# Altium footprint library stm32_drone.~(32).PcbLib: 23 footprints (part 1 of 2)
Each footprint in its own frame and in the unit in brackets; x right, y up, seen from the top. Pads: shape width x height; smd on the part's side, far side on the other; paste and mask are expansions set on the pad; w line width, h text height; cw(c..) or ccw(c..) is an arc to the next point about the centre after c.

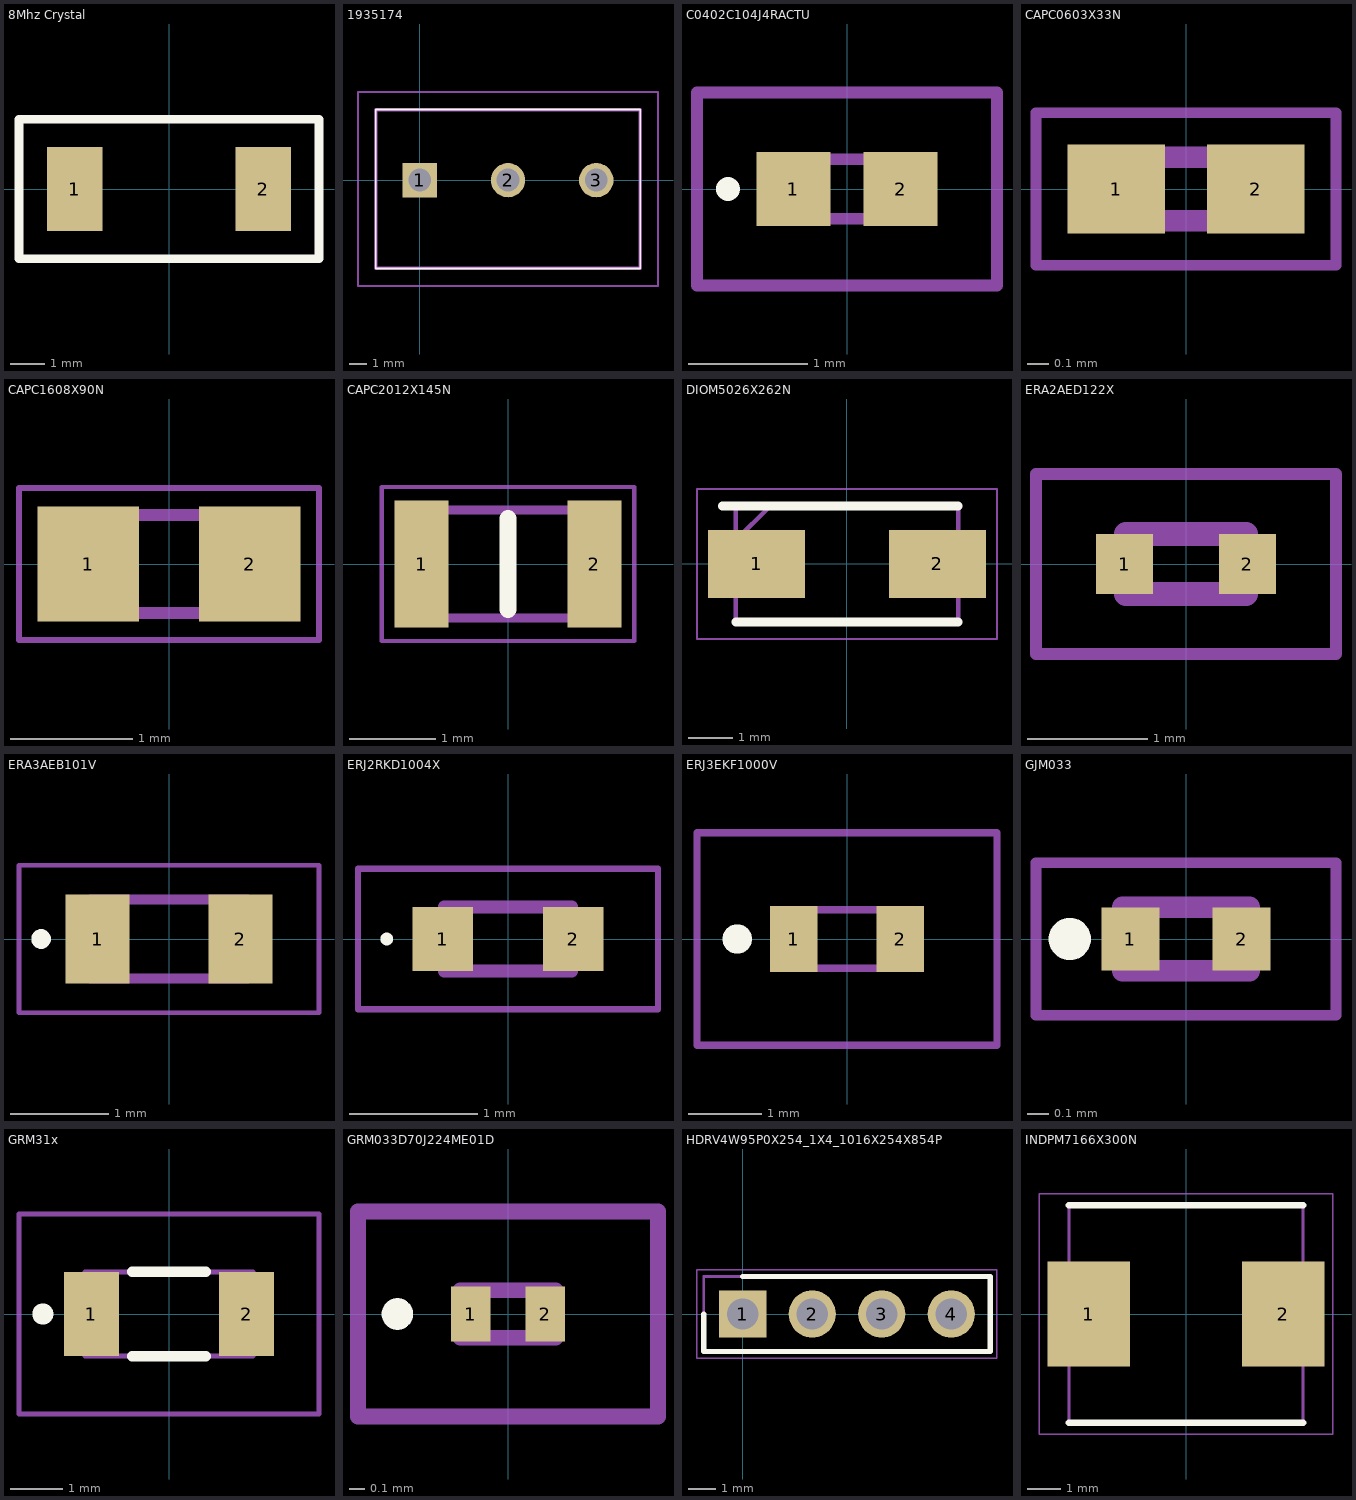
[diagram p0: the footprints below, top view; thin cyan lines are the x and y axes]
## 8Mhz Crystal [mm]
pads (2):
  rect 1.6x2.4 smd: 1(-2.7,0) 2(2.7,0)
Top Overlay:
  lines w0.25: -4.3,-2 -4.3,0 -4.3,2 4.3,2 4.3,-2 -4.3,-2
3D body "XTAL_H130A_RAL.step": height 1.09, standoff 0, extent -2.864,-2.089 2.864,2.089

## 1935174 [mm]
pads (3):
  rect 1.95x1.95 hole 1.3: 1(0,0)
  round 1.95 hole 1.3: 2(5,0) 3(10,0)
Top Overlay:
  lines w0.1: -2.5,-5 12.5,-5 12.5,4 -2.5,4 -2.5,-5
Mechanical 13:
  lines w0.2: -2.5,-5 12.5,-5 12.5,4 -2.5,4 -2.5,-5
Mechanical 15:
  lines w0.1: -3.5,-6 13.5,-6 13.5,5 -3.5,5 -3.5,-6
3D body "1935174.stp": height 11.63, standoff -3.27, extent -2.47,-5 12.93,4

## C0402C104J4RACTU [mm]
pads (2):
  rect 0.62x0.62 smd: 1(-0.45,0) 2(0.45,0)
Top Overlay:
  lines w0.1: -1,-0.05 ccw(c-1,0) -1,0.05 ccw(c-1,0) -1,-0.05
Mechanical 13:
  lines w0.1: -0.5,-0.25 -0.5,0.25 0.5,0.25 0.5,-0.25 -0.5,-0.25
Mechanical 15:
  lines w0.1: -1.26,-0.81 -1.26,0.81 1.26,0.81 1.26,-0.81 -1.26,-0.81
3D body "C0402C102J5GECTU.stp": height 0.55, standoff 0, extent -0.52,-0.28 0.53,0.27

## CAPC0603X33N [mm]
pads (2):
  rect 0.46x0.42 smd: 1(-0.33,0) 2(0.33,0)
Mechanical 13:
  lines w0.1: -0.3,-0.15 -0.3,0.15 0.3,0.15 0.3,-0.15 -0.3,-0.15
Mechanical 15:
  lines w0.05: -0.71,-0.36 -0.71,0.36 0.71,0.36 0.71,-0.36 -0.71,-0.36
3D body "GRM0335C1H101JA01D.stp": height 0.33, standoff 0, extent -0.3,-0.15 0.3,0.15

## CAPC1608X90N [mm]
pads (2):
  rect 0.83x0.94 smd: 1(-0.66,0) 2(0.66,0)
Mechanical 13:
  lines w0.1: -0.8,-0.4 0.8,-0.4 0.8,0.4 -0.8,0.4 -0.8,-0.4
Mechanical 15:
  lines w0.05: -1.225,-0.62 1.225,-0.62 1.225,0.62 -1.225,0.62 -1.225,-0.62
3D body "CC0603KRX5R8BB105.stp": height 0.9, standoff 0, extent -0.85,-0.45 0.85,0.45

## CAPC2012X145N [mm]
pads (2):
  rect 0.62x1.47 smd: 1(-1,0) 2(1,0)
Top Overlay:
  lines w0.2: 0,-0.525 0,0.525
Mechanical 13:
  lines w0.1: -1,-0.625 1,-0.625 1,0.625 -1,0.625 -1,-0.625
Mechanical 15:
  lines w0.05: -1.46,-0.89 1.46,-0.89 1.46,0.89 -1.46,0.89 -1.46,-0.89
3D body "C2012X5R1V226M125AC.stp": height 1.25, standoff 0, extent -1,-0.8 1,0.8

## DIOM5026X262N [mm]
pads (2):
  rect 2.2x1.55 smd: 1(-2.05,0) 2(2.05,0)
Top Overlay:
  lines w0.2: -2.825,1.312 2.52,1.312 ; -2.52,-1.312 2.52,-1.312
Mechanical 13:
  lines w0.1: -2.52,0.538 -1.745,1.312 ; -2.52,-1.312 2.52,-1.312 2.52,1.312 -2.52,1.312 -2.52,-1.312
Mechanical 15:
  lines w0.05: -3.4,-1.7 3.4,-1.7 3.4,1.7 -3.4,1.7 -3.4,-1.7
3D body "SS14.stp": height 2.62, standoff 0, extent -2.52,-1.312 2.52,1.312

## ERA2AED122X [mm]
pads (2):
  rect 0.475x0.5 smd: 1(-0.512,0) 2(0.512,0)
Mechanical 13:
  lines w0.2: -0.5,-0.25 0.5,-0.25 0.5,0.25 -0.5,0.25 -0.5,-0.25
Mechanical 15:
  lines w0.1: -1.25,-0.75 1.25,-0.75 1.25,0.75 -1.25,0.75 -1.25,-0.75
3D body "ERA-2AEB4990X.stp": height 0.35, standoff 0, extent -0.5,-0.25 0.5,0.25
3D body "0402_PAN.step": height 0.41, standoff 0, extent -0.546,-0.305 0.546,0.305

## ERA3AEB101V [mm]
pads (2):
  rect 0.65x0.9 smd: 1(-0.725,0) 2(0.725,0)
Top Overlay:
  lines w0.1: -1.3,-0.05 cw(c-1.3,0) -1.3,0.05 cw(c-1.3,0) -1.3,-0.05
Mechanical 13:
  lines w0.1: -0.8,-0.4 0.8,-0.4 0.8,0.4 -0.8,0.4 -0.8,-0.4
Mechanical 15:
  lines w0.05: -1.525,-0.75 1.525,-0.75 1.525,0.75 -1.525,0.75 -1.525,-0.75
3D body "ERA-3AEB333V.stp": height 0.45, standoff 0, extent -0.8,-0.4 0.8,0.4

## ERJ2RKD1004X [mm]
pads (2):
  rect 0.475x0.5 smd: 1(-0.512,0) 2(0.512,0)
Top Overlay:
  lines w0.05: -0.95,-0.025 cw(c-0.95,0) -0.95,0.025 cw(c-0.95,0) -0.95,-0.025
Mechanical 13:
  lines w0.1: -0.5,-0.25 0.5,-0.25 0.5,0.25 -0.5,0.25 -0.5,-0.25
Mechanical 15:
  lines w0.05: -1.175,-0.55 1.175,-0.55 1.175,0.55 -1.175,0.55 -1.175,-0.55
3D body "ERJ-2RKF2002X.stp": height 0.35, standoff 0, extent -0.5,-0.25 0.5,0.25

## ERJ3EKF1000V [mm]
pads (2):
  rect 0.65x0.9 smd: 1(-0.725,0) 2(0.725,0)
Top Overlay:
  lines w0.2: -1.5,-0.1 cw(c-1.5,0) -1.5,0.1 cw(c-1.5,0) -1.5,-0.1
Mechanical 13:
  lines w0.1: -0.8,-0.4 0.8,-0.4 0.8,0.4 -0.8,0.4 -0.8,-0.4
Mechanical 15:
  lines w0.1: -2.05,-1.45 2.05,-1.45 2.05,1.45 -2.05,1.45 -2.05,-1.45
3D body "ERJ-3GEYJ244V.stp": height 0.45, standoff 0, extent -0.8,-0.4 0.8,0.4

## GJM033 [mm]
pads (2):
  rect 0.275x0.3 smd: 1(-0.263,0) 2(0.263,0)
Top Overlay:
  lines w0.1: -0.55,-0.05 cw(c-0.55,0) -0.55,0.05 cw(c-0.55,0) -0.55,-0.05
Mechanical 13:
  lines w0.1: -0.3,-0.15 0.3,-0.15 0.3,0.15 -0.3,0.15 -0.3,-0.15
Mechanical 15:
  lines w0.05: -0.71,-0.36 0.71,-0.36 0.71,0.36 -0.71,0.36 -0.71,-0.36
3D body "GJM0335C1E2R0BB01D.stp": height 0.33, standoff 0, extent -0.3,-0.15 0.3,0.15

## GRM31x [mm]
pads (2):
  rect 1.05x1.6 smd: 1(-1.475,0) 2(1.475,0)
Top Overlay:
  lines w0.2: -0.7,-0.8 0.7,-0.8 ; -0.7,0.8 0.7,0.8 ; -2.4,-0.1 cw(c-2.4,0) -2.4,0.1 cw(c-2.4,0) -2.4,-0.1
Mechanical 13:
  lines w0.1: -1.6,-0.8 1.6,-0.8 1.6,0.8 -1.6,0.8 -1.6,-0.8
Mechanical 15:
  lines w0.1: -2.854,-1.902 2.854,-1.902 2.854,1.902 -2.854,1.902 -2.854,-1.902
3D body "GRM31CR60J107MEA8K.stp": height 1, standoff 0, extent -1.6,-0.8 1.6,0.8

## GRM033D70J224ME01D [mm]
pads (2):
  rect 0.25x0.35 smd: 1(-0.237,0) 2(0.237,0)
Top Overlay:
  lines w0.1: -0.7,-0.05 ccw(c-0.7,0) -0.7,0.05 ccw(c-0.7,0) -0.7,-0.05
Mechanical 13:
  lines w0.1: -0.3,-0.15 -0.3,0.15 0.3,0.15 0.3,-0.15 -0.3,-0.15
Mechanical 15:
  lines w0.1: -0.95,-0.65 -0.95,0.65 0.95,0.65 0.95,-0.65 -0.95,-0.65
3D body "GRM033C80J104KE15D.stp": height 0.3, standoff 0, extent -0.3,-0.15 0.3,0.15

## HDRV4W95P0X254_1X4_1016X254X854P [mm]
pads (4):
  rect 1.725x1.725 hole 1.15: 1(0,0)
  round 1.725 hole 1.15: 2(2.54,0) 3(5.08,0) 4(7.62,0)
Top Overlay:
  lines w0.2: -1.42,0 -1.42,-1.37 9.04,-1.37 9.04,1.37 0,1.37
Mechanical 13:
  lines w0.1: -1.42,-1.37 -1.42,1.37 9.04,1.37 9.04,-1.37 -1.42,-1.37
Mechanical 15:
  lines w0.05: -1.67,-1.62 -1.67,1.62 9.29,1.62 9.29,-1.62 -1.67,-1.62
3D body "61300411121.stp": height 8.54, standoff -3.2, extent -1.27,-1.27 8.89,1.27

## INDPM7166X300N [mm]
pads (2):
  rect 2.5x3.2 smd: 1(-2.95,0) 2(2.95,0)
Top Overlay:
  lines w0.2: -3.55,-3.3 3.55,-3.3 ; -3.55,3.3 3.55,3.3
Mechanical 13:
  lines w0.1: -3.55,-3.3 -3.55,3.3 3.55,3.3 3.55,-3.3 -3.55,-3.3
Mechanical 15:
  lines w0.05: -4.45,-3.65 -4.45,3.65 4.45,3.65 4.45,-3.65 -4.45,-3.65
3D body "ECS-MPIL0630-220MC.stp": height 3, standoff 0, extent -3.55,-3.3 3.55,3.3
